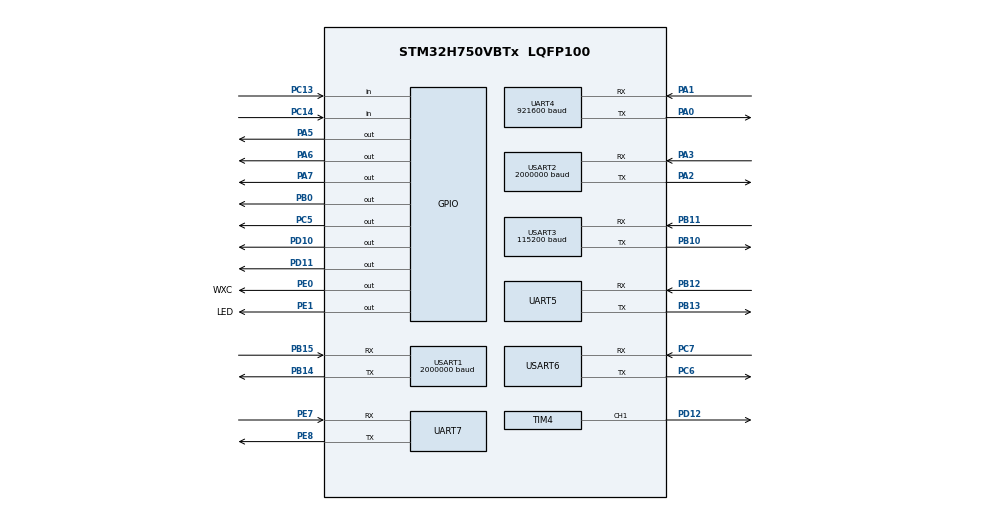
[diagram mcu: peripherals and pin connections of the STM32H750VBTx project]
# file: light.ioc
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CORTEX_M7.default_mode_Activation=1
Mcu.Family=STM32H7
Mcu.Name=STM32H750VBTx
Mcu.Package=LQFP100
NVIC.PriorityGroup=NVIC_PRIORITYGROUP_4
NVIC.UART7_IRQn=true\:0\:0\:true\:false\:true\:true\:true\:true
PA0.Mode=Asynchronous
PA0.Signal=UART4_TX
PA1.Mode=Asynchronous
PA1.Signal=UART4_RX
PA13\ (JTMS/SWDIO).Mode=Serial_Wire
PA13\ (JTMS/SWDIO).Signal=DEBUG_JTMS-SWDIO
PA14\ (JTCK/SWCLK).Mode=Serial_Wire
PA14\ (JTCK/SWCLK).Signal=DEBUG_JTCK-SWCLK
PA2.Mode=Asynchronous
PA2.Signal=USART2_TX
PA3.Mode=Asynchronous
PA3.Signal=USART2_RX
PA5.Signal=GPIO_Output
PA6.Signal=GPIO_Output
PA7.Signal=GPIO_Output
PB0.GPIO_ModeDefaultOutputPP=GPIO_MODE_OUTPUT_OD
PB0.GPIO_PuPd=GPIO_NOPULL
PB0.GPIO_Speed=GPIO_SPEED_FREQ_VERY_HIGH
PB0.PinState=GPIO_PIN_SET
PB0.Signal=GPIO_Output
PB10.Mode=Asynchronous
PB10.Signal=USART3_TX
PB11.Mode=Asynchronous
PB11.Signal=USART3_RX
PB12.Mode=Asynchronous
PB12.Signal=UART5_RX
PB13.Mode=Asynchronous
PB13.Signal=UART5_TX
PB14.Mode=Asynchronous
PB14.Signal=USART1_TX
PB15.Mode=Asynchronous
PB15.Signal=USART1_RX
PC13.GPIO_PuPd=GPIO_PULLUP
PC13.Signal=GPIO_Input
PC14-OSC32_IN\ (OSC32_IN).GPIO_PuPd=GPIO_PULLUP
PC14-OSC32_IN\ (OSC32_IN).Signal=GPIO_Input
PC5.GPIO_ModeDefaultOutputPP=GPIO_MODE_OUTPUT_OD
PC5.GPIO_PuPd=GPIO_NOPULL
PC5.GPIO_Speed=GPIO_SPEED_FREQ_VERY_HIGH
PC5.PinState=GPIO_PIN_SET
PC5.Signal=GPIO_Output
PC6.Mode=Asynchronous
PC6.Signal=USART6_TX
PC7.Mode=Asynchronous
PC7.Signal=USART6_RX
PD10.GPIO_ModeDefaultOutputPP=GPIO_MODE_OUTPUT_OD
PD10.GPIO_PuPd=GPIO_PULLUP
PD10.GPIO_Speed=GPIO_SPEED_FREQ_VERY_HIGH
PD10.PinState=GPIO_PIN_SET
PD10.Signal=GPIO_Output
PD11.GPIO_ModeDefaultOutputPP=GPIO_MODE_OUTPUT_OD
PD11.GPIO_PuPd=GPIO_PULLUP
PD11.GPIO_Speed=GPIO_SPEED_FREQ_VERY_HIGH
PD11.PinState=GPIO_PIN_SET
PD11.Signal=GPIO_Output
PD12.Signal=S_TIM4_CH1
PE0.GPIO_Label=WXC
PE0.GPIO_Speed=GPIO_SPEED_FREQ_LOW
PE0.Signal=GPIO_Output
PE1.GPIO_Label=LED
PE1.GPIO_Speed=GPIO_SPEED_FREQ_LOW
PE1.Signal=GPIO_Output
PE7.GPIO_Speed=GPIO_SPEED_FREQ_VERY_HIGH
PE7.Mode=Asynchronous
PE7.Signal=UART7_RX
PE8.GPIO_Speed=GPIO_SPEED_FREQ_VERY_HIGH
PE8.Mode=Asynchronous
PE8.Signal=UART7_TX
PH0-OSC_IN\ (PH0).Mode=HSE-External-Oscillator
PH0-OSC_IN\ (PH0).Signal=RCC_OSC_IN
PH1-OSC_OUT\ (PH1).Mode=HSE-External-Oscillator
PH1-OSC_OUT\ (PH1).Signal=RCC_OSC_OUT
ProjectManager.HeapSize=0x3000
ProjectManager.StackSize=0xE00
ProjectManager.TargetToolchain=STM32CubeIDE
RCC.ADCFreq_Value=75000000
RCC.APB1Freq_Value=120000000
RCC.APB2Freq_Value=120000000
RCC.APB3Freq_Value=120000000
RCC.APB4Freq_Value=120000000
RCC.CortexFreq_Value=480000000
RCC.D1PPRE=RCC_APB3_DIV2
RCC.D2PPRE1=RCC_APB1_DIV2
RCC.D2PPRE2=RCC_APB2_DIV2
RCC.D3PPRE=RCC_APB4_DIV2
RCC.DIVM1=5
RCC.DIVM2=2
RCC.DIVN1=192
RCC.DIVN2=12
RCC.HCLKFreq_Value=240000000
RCC.HPRE=RCC_HCLK_DIV2
RCC.PLL2FRACN=0
RCC.PLL3FRACN=0
RCC.PLLFRACN=0
RCC.PLLSourceVirtual=RCC_PLLSOURCE_HSE
RCC.SYSCLKFreq_VALUE=480000000
RCC.SYSCLKSource=RCC_SYSCLKSOURCE_PLLCLK
RCC.USBFreq_Value=480000000
SH.S_TIM4_CH1.0=TIM4_CH1,PWM Generation1 CH1
TIM15.Period=1000
TIM15.Prescaler=2400
TIM4.Channel-PWM\ Generation1\ CH1=TIM_CHANNEL_1
TIM4.OCPolarity_1=TIM_OCPOLARITY_LOW
TIM4.Period=1000
TIM4.Prescaler=240
TIM6.Prescaler=240
TIM7.Period=1000
TIM7.Prescaler=240
UART4.BaudRate=921600
USART1.BaudRate=2000000
USART1.VirtualMode-Asynchronous=VM_ASYNC
USART2.BaudRate=2000000
USART2.VirtualMode-Asynchronous=VM_ASYNC
USART3.BaudRate=115200
USART3.VirtualMode-Asynchronous=VM_ASYNC
USART6.VirtualMode=VM_ASYNC
VP_MEMORYMAP_VS_MEMORYMAP.Mode=CurAppReg
VP_TIM15_VS_ClockSourceINT.Mode=Internal
VP_TIM4_VS_ClockSourceINT.Mode=Internal
VP_TIM6_VS_ClockSourceINT.Mode=Enable_Timer
VP_TIM7_VS_ClockSourceINT.Mode=Enable_Timer
board=custom

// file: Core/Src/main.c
/* USER CODE BEGIN Header */
/**
  ******************************************************************************
  * @file           : main.c
  * @brief          : Main program body
  ******************************************************************************
  * @attention
  *
  * Copyright (c) 2025 STMicroelectronics.
  * All rights reserved.
  *
  * This software is licensed under terms that can be found in the LICENSE file
  * in the root directory of this software component.
  * If no LICENSE file comes with this software, it is provided AS-IS.
  *
  ******************************************************************************
  */
/* USER CODE END Header */
#include "main.h"

/* USER CODE BEGIN Includes */
#include "App.h"
/* USER CODE END Includes */

TIM_HandleTypeDef htim4;
TIM_HandleTypeDef htim6;
TIM_HandleTypeDef htim7;
TIM_HandleTypeDef htim15;

UART_HandleTypeDef huart4;
UART_HandleTypeDef huart5;
UART_HandleTypeDef huart7;
UART_HandleTypeDef huart1;
UART_HandleTypeDef huart2;
UART_HandleTypeDef huart3;
UART_HandleTypeDef huart6;
DMA_HandleTypeDef hdma_usart6_tx;

void SystemClock_Config(void);
static void MPU_Config(void);
static void MX_GPIO_Init(void);
static void MX_TIM6_Init(void);
static void MX_USART1_UART_Init(void);
static void MX_UART7_Init(void);
static void MX_TIM4_Init(void);
static void MX_TIM7_Init(void);
static void MX_USART2_UART_Init(void);
static void MX_UART4_Init(void);
static void MX_TIM15_Init(void);
static void MX_USART3_UART_Init(void);
static void MX_UART5_Init(void);
static void MX_USART6_UART_Init(void);

int main(void)
{

  /* MPU Configuration--------------------------------------------------------*/
  MPU_Config();

  /* MCU Configuration--------------------------------------------------------*/

  /* Reset of all peripherals, Initializes the Flash interface and the Systick. */
  HAL_Init();

  /* Configure the system clock */
  SystemClock_Config();

  /* Initialize all configured peripherals */
  MX_GPIO_Init();
  MX_TIM6_Init();
  MX_USART1_UART_Init();
  MX_UART7_Init();
  MX_TIM4_Init();
  MX_TIM7_Init();
  MX_USART2_UART_Init();
  MX_UART4_Init();
  MX_TIM15_Init();
  MX_USART3_UART_Init();
  MX_UART5_Init();
  MX_USART6_UART_Init();

  /* Application start */
  Init();
  Main();

  while (1) { }
}

void SystemClock_Config(void)
{
  RCC_OscInitTypeDef RCC_OscInitStruct = {0};
  RCC_ClkInitTypeDef RCC_ClkInitStruct = {0};

  /** Supply configuration update enable
  */
  HAL_PWREx_ConfigSupply(PWR_LDO_SUPPLY);

  /** Configure the main internal regulator output voltage
  */
  __HAL_PWR_VOLTAGESCALING_CONFIG(PWR_REGULATOR_VOLTAGE_SCALE0);

  while(!__HAL_PWR_GET_FLAG(PWR_FLAG_VOSRDY)) {}

  /** Initializes the RCC Oscillators according to the specified parameters
  * in the RCC_OscInitTypeDef structure.
  */
  RCC_OscInitStruct.OscillatorType = RCC_OSCILLATORTYPE_HSE;
  RCC_OscInitStruct.HSEState = RCC_HSE_ON;
  RCC_OscInitStruct.PLL.PLLState = RCC_PLL_ON;
  RCC_OscInitStruct.PLL.PLLSource = RCC_PLLSOURCE_HSE;
  RCC_OscInitStruct.PLL.PLLM = 5;
  RCC_OscInitStruct.PLL.PLLN = 192;
  RCC_OscInitStruct.PLL.PLLP = 2;
  RCC_OscInitStruct.PLL.PLLQ = 2;
  RCC_OscInitStruct.PLL.PLLR = 2;
  RCC_OscInitStruct.PLL.PLLRGE = RCC_PLL1VCIRANGE_2;
  RCC_OscInitStruct.PLL.PLLVCOSEL = RCC_PLL1VCOWIDE;
  RCC_OscInitStruct.PLL.PLLFRACN = 0;
  if (HAL_RCC_OscConfig(&RCC_OscInitStruct) != HAL_OK)
  {
    Error_Handler();
  }

  /** Initializes the CPU, AHB and APB buses clocks
  */
  RCC_ClkInitStruct.ClockType = RCC_CLOCKTYPE_HCLK|RCC_CLOCKTYPE_SYSCLK
                              |RCC_CLOCKTYPE_PCLK1|RCC_CLOCKTYPE_PCLK2
                              |RCC_CLOCKTYPE_D3PCLK1|RCC_CLOCKTYPE_D1PCLK1;
  RCC_ClkInitStruct.SYSCLKSource = RCC_SYSCLKSOURCE_PLLCLK;
  RCC_ClkInitStruct.SYSCLKDivider = RCC_SYSCLK_DIV1;
  RCC_ClkInitStruct.AHBCLKDivider = RCC_HCLK_DIV2;
  RCC_ClkInitStruct.APB3CLKDivider = RCC_APB3_DIV2;
  RCC_ClkInitStruct.APB1CLKDivider = RCC_APB1_DIV2;
  RCC_ClkInitStruct.APB2CLKDivider = RCC_APB2_DIV2;
  RCC_ClkInitStruct.APB4CLKDivider = RCC_APB4_DIV2;

  if (HAL_RCC_ClockConfig(&RCC_ClkInitStruct, FLASH_LATENCY_4) != HAL_OK)
  {
    Error_Handler();
  }
}

static void MX_TIM4_Init(void)
{

  TIM_ClockConfigTypeDef sClockSourceConfig = {0};
  TIM_MasterConfigTypeDef sMasterConfig = {0};
  TIM_OC_InitTypeDef sConfigOC = {0};

  htim4.Instance = TIM4;
  htim4.Init.Prescaler = 240;
  htim4.Init.CounterMode = TIM_COUNTERMODE_UP;
  htim4.Init.Period = 1000;
  htim4.Init.ClockDivision = TIM_CLOCKDIVISION_DIV1;
  htim4.Init.AutoReloadPreload = TIM_AUTORELOAD_PRELOAD_DISABLE;
  if (HAL_TIM_Base_Init(&htim4) != HAL_OK)
  {
    Error_Handler();
  }
  sClockSourceConfig.ClockSource = TIM_CLOCKSOURCE_INTERNAL;
  if (HAL_TIM_ConfigClockSource(&htim4, &sClockSourceConfig) != HAL_OK)
  {
    Error_Handler();
  }
  if (HAL_TIM_PWM_Init(&htim4) != HAL_OK)
  {
    Error_Handler();
  }
  sMasterConfig.MasterOutputTrigger = TIM_TRGO_RESET;
  sMasterConfig.MasterSlaveMode = TIM_MASTERSLAVEMODE_DISABLE;
  if (HAL_TIMEx_MasterConfigSynchronization(&htim4, &sMasterConfig) != HAL_OK)
  {
    Error_Handler();
  }
  sConfigOC.OCMode = TIM_OCMODE_PWM1;
  sConfigOC.Pulse = 0;
  sConfigOC.OCPolarity = TIM_OCPOLARITY_HIGH;
  sConfigOC.OCFastMode = TIM_OCFAST_DISABLE;
  if (HAL_TIM_PWM_ConfigChannel(&htim4, &sConfigOC, TIM_CHANNEL_1) != HAL_OK)
  {
    Error_Handler();
  }
  HAL_TIM_MspPostInit(&htim4);

}

static void MX_TIM6_Init(void)
{

  TIM_MasterConfigTypeDef sMasterConfig = {0};

  htim6.Instance = TIM6;
  htim6.Init.Prescaler = 240;
  htim6.Init.CounterMode = TIM_COUNTERMODE_UP;
  htim6.Init.Period = 65535;
  htim6.Init.AutoReloadPreload = TIM_AUTORELOAD_PRELOAD_DISABLE;
  if (HAL_TIM_Base_Init(&htim6) != HAL_OK)
  {
    Error_Handler();
  }
  sMasterConfig.MasterOutputTrigger = TIM_TRGO_RESET;
  sMasterConfig.MasterSlaveMode = TIM_MASTERSLAVEMODE_DISABLE;
  if (HAL_TIMEx_MasterConfigSynchronization(&htim6, &sMasterConfig) != HAL_OK)
  {
    Error_Handler();
  }

}

static void MX_TIM7_Init(void)
{

  TIM_MasterConfigTypeDef sMasterConfig = {0};

  htim7.Instance = TIM7;
  htim7.Init.Prescaler = 240;
  htim7.Init.CounterMode = TIM_COUNTERMODE_UP;
  htim7.Init.Period = 1000;
  htim7.Init.AutoReloadPreload = TIM_AUTORELOAD_PRELOAD_DISABLE;
  if (HAL_TIM_Base_Init(&htim7) != HAL_OK)
  {
    Error_Handler();
  }
  sMasterConfig.MasterOutputTrigger = TIM_TRGO_RESET;
  sMasterConfig.MasterSlaveMode = TIM_MASTERSLAVEMODE_DISABLE;
  if (HAL_TIMEx_MasterConfigSynchronization(&htim7, &sMasterConfig) != HAL_OK)
  {
    Error_Handler();
  }

}

static void MX_TIM15_Init(void)
{

  TIM_ClockConfigTypeDef sClockSourceConfig = {0};
  TIM_MasterConfigTypeDef sMasterConfig = {0};

  htim15.Instance = TIM15;
  htim15.Init.Prescaler = 2400;
  htim15.Init.CounterMode = TIM_COUNTERMODE_UP;
  htim15.Init.Period = 1000;
  htim15.Init.ClockDivision = TIM_CLOCKDIVISION_DIV1;
  htim15.Init.RepetitionCounter = 0;
  htim15.Init.AutoReloadPreload = TIM_AUTORELOAD_PRELOAD_DISABLE;
  if (HAL_TIM_Base_Init(&htim15) != HAL_OK)
  {
    Error_Handler();
  }
  sClockSourceConfig.ClockSource = TIM_CLOCKSOURCE_INTERNAL;
  if (HAL_TIM_ConfigClockSource(&htim15, &sClockSourceConfig) != HAL_OK)
  {
    Error_Handler();
  }
  sMasterConfig.MasterOutputTrigger = TIM_TRGO_RESET;
  sMasterConfig.MasterSlaveMode = TIM_MASTERSLAVEMODE_DISABLE;
  if (HAL_TIMEx_MasterConfigSynchronization(&htim15, &sMasterConfig) != HAL_OK)
  {
    Error_Handler();
  }

}

static void MX_UART4_Init(void)
{

  huart4.Instance = UART4;
  huart4.Init.BaudRate = 921600;
  huart4.Init.WordLength = UART_WORDLENGTH_8B;
  huart4.Init.StopBits = UART_STOPBITS_1;
  huart4.Init.Parity = UART_PARITY_NONE;
  huart4.Init.Mode = UART_MODE_TX_RX;
  huart4.Init.HwFlowCtl = UART_HWCONTROL_NONE;
  huart4.Init.OverSampling = UART_OVERSAMPLING_16;
  huart4.Init.OneBitSampling = UART_ONE_BIT_SAMPLE_DISABLE;
  huart4.Init.ClockPrescaler = UART_PRESCALER_DIV1;
  huart4.AdvancedInit.AdvFeatureInit = UART_ADVFEATURE_NO_INIT;
  if (HAL_UART_Init(&huart4) != HAL_OK)
  {
    Error_Handler();
  }
  if (HAL_UARTEx_SetTxFifoThreshold(&huart4, UART_TXFIFO_THRESHOLD_1_8) != HAL_OK)
  {
    Error_Handler();
  }
  if (HAL_UARTEx_SetRxFifoThreshold(&huart4, UART_RXFIFO_THRESHOLD_1_8) != HAL_OK)
  {
    Error_Handler();
  }
  if (HAL_UARTEx_DisableFifoMode(&huart4) != HAL_OK)
  {
    Error_Handler();
  }

}

static void MX_UART5_Init(void)
{

  huart5.Instance = UART5;
  huart5.Init.BaudRate = 115200;
  huart5.Init.WordLength = UART_WORDLENGTH_8B;
  huart5.Init.StopBits = UART_STOPBITS_1;
  huart5.Init.Parity = UART_PARITY_NONE;
  huart5.Init.Mode = UART_MODE_TX_RX;
  huart5.Init.HwFlowCtl = UART_HWCONTROL_NONE;
  huart5.Init.OverSampling = UART_OVERSAMPLING_16;
  huart5.Init.OneBitSampling = UART_ONE_BIT_SAMPLE_DISABLE;
  huart5.Init.ClockPrescaler = UART_PRESCALER_DIV1;
  huart5.AdvancedInit.AdvFeatureInit = UART_ADVFEATURE_NO_INIT;
  if (HAL_UART_Init(&huart5) != HAL_OK)
  {
    Error_Handler();
  }
  if (HAL_UARTEx_SetTxFifoThreshold(&huart5, UART_TXFIFO_THRESHOLD_1_8) != HAL_OK)
  {
    Error_Handler();
  }
  if (HAL_UARTEx_SetRxFifoThreshold(&huart5, UART_RXFIFO_THRESHOLD_1_8) != HAL_OK)
  {
    Error_Handler();
  }
  if (HAL_UARTEx_DisableFifoMode(&huart5) != HAL_OK)
  {
    Error_Handler();
  }

}

static void MX_UART7_Init(void)
{

  huart7.Instance = UART7;
  huart7.Init.BaudRate = 115200;
  huart7.Init.WordLength = UART_WORDLENGTH_8B;
  huart7.Init.StopBits = UART_STOPBITS_1;
  huart7.Init.Parity = UART_PARITY_NONE;
  huart7.Init.Mode = UART_MODE_TX_RX;
  huart7.Init.HwFlowCtl = UART_HWCONTROL_NONE;
  huart7.Init.OverSampling = UART_OVERSAMPLING_16;
  huart7.Init.OneBitSampling = UART_ONE_BIT_SAMPLE_DISABLE;
  huart7.Init.ClockPrescaler = UART_PRESCALER_DIV1;
  huart7.AdvancedInit.AdvFeatureInit = UART_ADVFEATURE_NO_INIT;
  if (HAL_UART_Init(&huart7) != HAL_OK)
  {
    Error_Handler();
  }
  if (HAL_UARTEx_SetTxFifoThreshold(&huart7, UART_TXFIFO_THRESHOLD_1_8) != HAL_OK)
  {
    Error_Handler();
  }
  if (HAL_UARTEx_SetRxFifoThreshold(&huart7, UART_RXFIFO_THRESHOLD_1_8) != HAL_OK)
  {
    Error_Handler();
  }
  if (HAL_UARTEx_DisableFifoMode(&huart7) != HAL_OK)
  {
    Error_Handler();
  }

}

static void MX_USART1_UART_Init(void)
{

  huart1.Instance = USART1;
  huart1.Init.BaudRate = 115200;
  huart1.Init.WordLength = UART_WORDLENGTH_8B;
  huart1.Init.StopBits = UART_STOPBITS_1;
  huart1.Init.Parity = UART_PARITY_NONE;
  huart1.Init.Mode = UART_MODE_TX_RX;
  huart1.Init.HwFlowCtl = UART_HWCONTROL_NONE;
  huart1.Init.OverSampling = UART_OVERSAMPLING_16;
  huart1.Init.OneBitSampling = UART_ONE_BIT_SAMPLE_DISABLE;
  huart1.Init.ClockPrescaler = UART_PRESCALER_DIV1;
  huart1.AdvancedInit.AdvFeatureInit = UART_ADVFEATURE_NO_INIT;
  if (HAL_UART_Init(&huart1) != HAL_OK)
  {
    Error_Handler();
  }
  if (HAL_UARTEx_SetTxFifoThreshold(&huart1, UART_TXFIFO_THRESHOLD_1_8) != HAL_OK)
  {
    Error_Handler();
  }
  if (HAL_UARTEx_SetRxFifoThreshold(&huart1, UART_RXFIFO_THRESHOLD_1_8) != HAL_OK)
  {
    Error_Handler();
  }
  if (HAL_UARTEx_DisableFifoMode(&huart1) != HAL_OK)
  {
    Error_Handler();
  }

}

static void MX_USART2_UART_Init(void)
{

  huart2.Instance = USART2;
  huart2.Init.BaudRate = 115200;
  huart2.Init.WordLength = UART_WORDLENGTH_8B;
  huart2.Init.StopBits = UART_STOPBITS_1;
  huart2.Init.Parity = UART_PARITY_NONE;
  huart2.Init.Mode = UART_MODE_TX_RX;
  huart2.Init.HwFlowCtl = UART_HWCONTROL_NONE;
  huart2.Init.OverSampling = UART_OVERSAMPLING_16;
  huart2.Init.OneBitSampling = UART_ONE_BIT_SAMPLE_DISABLE;
  huart2.Init.ClockPrescaler = UART_PRESCALER_DIV1;
  huart2.AdvancedInit.AdvFeatureInit = UART_ADVFEATURE_NO_INIT;
  if (HAL_UART_Init(&huart2) != HAL_OK)
  {
    Error_Handler();
  }
  if (HAL_UARTEx_SetTxFifoThreshold(&huart2, UART_TXFIFO_THRESHOLD_1_8) != HAL_OK)
  {
    Error_Handler();
  }
  if (HAL_UARTEx_SetRxFifoThreshold(&huart2, UART_RXFIFO_THRESHOLD_1_8) != HAL_OK)
  {
    Error_Handler();
  }
  if (HAL_UARTEx_DisableFifoMode(&huart2) != HAL_OK)
  {
    Error_Handler();
  }

}

static void MX_USART3_UART_Init(void)
{

  huart3.Instance = USART3;
  huart3.Init.BaudRate = 115200;
  huart3.Init.WordLength = UART_WORDLENGTH_8B;
  huart3.Init.StopBits = UART_STOPBITS_1;
  huart3.Init.Parity = UART_PARITY_NONE;
  huart3.Init.Mode = UART_MODE_TX_RX;
  huart3.Init.HwFlowCtl = UART_HWCONTROL_NONE;
  huart3.Init.OverSampling = UART_OVERSAMPLING_16;
  huart3.Init.OneBitSampling = UART_ONE_BIT_SAMPLE_DISABLE;
  huart3.Init.ClockPrescaler = UART_PRESCALER_DIV1;
  huart3.AdvancedInit.AdvFeatureInit = UART_ADVFEATURE_NO_INIT;
  if (HAL_UART_Init(&huart3) != HAL_OK)
  {
    Error_Handler();
  }
  if (HAL_UARTEx_SetTxFifoThreshold(&huart3, UART_TXFIFO_THRESHOLD_1_8) != HAL_OK)
  {
    Error_Handler();
  }
  if (HAL_UARTEx_SetRxFifoThreshold(&huart3, UART_RXFIFO_THRESHOLD_1_8) != HAL_OK)
  {
    Error_Handler();
  }
  if (HAL_UARTEx_DisableFifoMode(&huart3) != HAL_OK)
  {
    Error_Handler();
  }

}

static void MX_USART6_UART_Init(void)
{

  huart6.Instance = USART6;
  huart6.Init.BaudRate = 115200;
  huart6.Init.WordLength = UART_WORDLENGTH_8B;
  huart6.Init.StopBits = UART_STOPBITS_1;
  huart6.Init.Parity = UART_PARITY_NONE;
  huart6.Init.Mode = UART_MODE_TX_RX;
  huart6.Init.HwFlowCtl = UART_HWCONTROL_NONE;
  huart6.Init.OverSampling = UART_OVERSAMPLING_16;
  huart6.Init.OneBitSampling = UART_ONE_BIT_SAMPLE_DISABLE;
  huart6.Init.ClockPrescaler = UART_PRESCALER_DIV1;
  huart6.AdvancedInit.AdvFeatureInit = UART_ADVFEATURE_NO_INIT;
  if (HAL_UART_Init(&huart6) != HAL_OK)
  {
    Error_Handler();
  }
  if (HAL_UARTEx_SetTxFifoThreshold(&huart6, UART_TXFIFO_THRESHOLD_1_8) != HAL_OK)
  {
    Error_Handler();
  }
  if (HAL_UARTEx_SetRxFifoThreshold(&huart6, UART_RXFIFO_THRESHOLD_1_8) != HAL_OK)
  {
    Error_Handler();
  }
  if (HAL_UARTEx_DisableFifoMode(&huart6) != HAL_OK)
  {
    Error_Handler();
  }

}

static void MX_GPIO_Init(void)
{
  GPIO_InitTypeDef GPIO_InitStruct = {0};

  /* GPIO Ports Clock Enable */
  __HAL_RCC_GPIOC_CLK_ENABLE();
  __HAL_RCC_GPIOH_CLK_ENABLE();
  __HAL_RCC_GPIOA_CLK_ENABLE();
  __HAL_RCC_GPIOB_CLK_ENABLE();
  __HAL_RCC_GPIOE_CLK_ENABLE();
  __HAL_RCC_GPIOD_CLK_ENABLE();

  /*Configure GPIO pin Output Level */
  HAL_GPIO_WritePin(GPIOA, GPIO_PIN_5|GPIO_PIN_6|GPIO_PIN_7, GPIO_PIN_RESET);

  /*Configure GPIO pin Output Level */
  HAL_GPIO_WritePin(GPIOC, GPIO_PIN_5, GPIO_PIN_SET);

  /*Configure GPIO pin Output Level */
  HAL_GPIO_WritePin(GPIOB, GPIO_PIN_0, GPIO_PIN_SET);

  /*Configure GPIO pin Output Level */
  HAL_GPIO_WritePin(GPIOE, WXC_Pin|LED_Pin, GPIO_PIN_RESET);

  /*Configure GPIO pins : PC13 PC14 */
  GPIO_InitStruct.Pin = GPIO_PIN_13|GPIO_PIN_14;
  GPIO_InitStruct.Mode = GPIO_MODE_INPUT;
  GPIO_InitStruct.Pull = GPIO_PULLUP;
  HAL_GPIO_Init(GPIOC, &GPIO_InitStruct);

  /*Configure GPIO pins : PA5 PA6 PA7 */
  GPIO_InitStruct.Pin = GPIO_PIN_5|GPIO_PIN_6|GPIO_PIN_7;
  GPIO_InitStruct.Mode = GPIO_MODE_OUTPUT_PP;
  GPIO_InitStruct.Pull = GPIO_NOPULL;
  GPIO_InitStruct.Speed = GPIO_SPEED_FREQ_LOW;
  HAL_GPIO_Init(GPIOA, &GPIO_InitStruct);

  /*Configure GPIO pin : PC5 */
  GPIO_InitStruct.Pin = GPIO_PIN_5;
  GPIO_InitStruct.Mode = GPIO_MODE_OUTPUT_OD;
  GPIO_InitStruct.Pull = GPIO_NOPULL;
  GPIO_InitStruct.Speed = GPIO_SPEED_FREQ_VERY_HIGH;
  HAL_GPIO_Init(GPIOC, &GPIO_InitStruct);

  /*Configure GPIO pin : PB0 */
  GPIO_InitStruct.Pin = GPIO_PIN_0;
  GPIO_InitStruct.Mode = GPIO_MODE_OUTPUT_OD;
  GPIO_InitStruct.Pull = GPIO_NOPULL;
  GPIO_InitStruct.Speed = GPIO_SPEED_FREQ_VERY_HIGH;
  HAL_GPIO_Init(GPIOB, &GPIO_InitStruct);

  /*Configure GPIO pins : PD10 PD11 */
  GPIO_InitStruct.Pin = GPIO_PIN_10|GPIO_PIN_11;
  GPIO_InitStruct.Mode = GPIO_MODE_OUTPUT_PP;
  GPIO_InitStruct.Pull = GPIO_NOPULL;
  GPIO_InitStruct.Speed = GPIO_SPEED_FREQ_LOW;
  HAL_GPIO_Init(GPIOD, &GPIO_InitStruct);

  /*Configure GPIO pins : WXC_Pin LED_Pin */
  GPIO_InitStruct.Pin = WXC_Pin|LED_Pin;
  GPIO_InitStruct.Mode = GPIO_MODE_OUTPUT_PP;
  GPIO_InitStruct.Pull = GPIO_NOPULL;
  GPIO_InitStruct.Speed = GPIO_SPEED_FREQ_LOW;
  HAL_GPIO_Init(GPIOE, &GPIO_InitStruct);

  /* USER CODE BEGIN MX_GPIO_Init_2 */
  /* Pusher motor pins PD14, PD15 */
  GPIO_InitStruct.Pin = GPIO_PIN_14 | GPIO_PIN_15;
  GPIO_InitStruct.Mode = GPIO_MODE_OUTPUT_PP; // �������ģʽ
  GPIO_InitStruct.Pull = GPIO_NOPULL;
  GPIO_InitStruct.Speed = GPIO_SPEED_FREQ_LOW;
  HAL_GPIO_Init(GPIOD, &GPIO_InitStruct);

  // ȷ����ʼ״̬�ǵ͵�ƽ (ֹͣ)
  HAL_GPIO_WritePin(GPIOD, GPIO_PIN_14 | GPIO_PIN_15, GPIO_PIN_RESET);
  HAL_GPIO_WritePin(GPIOD, GPIO_PIN_10|GPIO_PIN_11, GPIO_PIN_RESET);

  /* USER CODE END MX_GPIO_Init_2 */
  /*Configure GPIO pins : PD1 PD2*/
  GPIO_InitStruct.Pin = GPIO_PIN_1;
  GPIO_InitStruct.Mode = GPIO_MODE_INPUT;
  GPIO_InitStruct.Pull = GPIO_PULLDOWN;
  HAL_GPIO_Init(GPIOD, &GPIO_InitStruct);

  GPIO_InitStruct.Pin = GPIO_PIN_2;
  GPIO_InitStruct.Mode = GPIO_MODE_OUTPUT_PP;
  GPIO_InitStruct.Pull = GPIO_NOPULL;
  GPIO_InitStruct.Speed = GPIO_SPEED_FREQ_LOW;
  HAL_GPIO_Init(GPIOD, &GPIO_InitStruct);
  HAL_GPIO_WritePin(GPIOD, GPIO_PIN_2, GPIO_PIN_SET); // ��ʼ������
}

 /* MPU Configuration */

void MPU_Config(void)
{
  MPU_Region_InitTypeDef MPU_InitStruct = {0};

  /* Disables the MPU */
  HAL_MPU_Disable();

  /** Initializes and configures the Region and the memory to be protected
  */
  MPU_InitStruct.Enable = MPU_REGION_ENABLE;
  MPU_InitStruct.Number = MPU_REGION_NUMBER0;
  MPU_InitStruct.BaseAddress = 0x0;
  MPU_InitStruct.Size = MPU_REGION_SIZE_4GB;
  MPU_InitStruct.SubRegionDisable = 0x87;
  MPU_InitStruct.TypeExtField = MPU_TEX_LEVEL0;
  MPU_InitStruct.AccessPermission = MPU_REGION_NO_ACCESS;
  MPU_InitStruct.DisableExec = MPU_INSTRUCTION_ACCESS_DISABLE;
  MPU_InitStruct.IsShareable = MPU_ACCESS_SHAREABLE;
  MPU_InitStruct.IsCacheable = MPU_ACCESS_NOT_CACHEABLE;
  MPU_InitStruct.IsBufferable = MPU_ACCESS_NOT_BUFFERABLE;

  HAL_MPU_ConfigRegion(&MPU_InitStruct);
  /* Enables the MPU */
  HAL_MPU_Enable(MPU_PRIVILEGED_DEFAULT);

}

void Error_Handler(void)
{
  __disable_irq();
  while (1)
  {
  }
}
